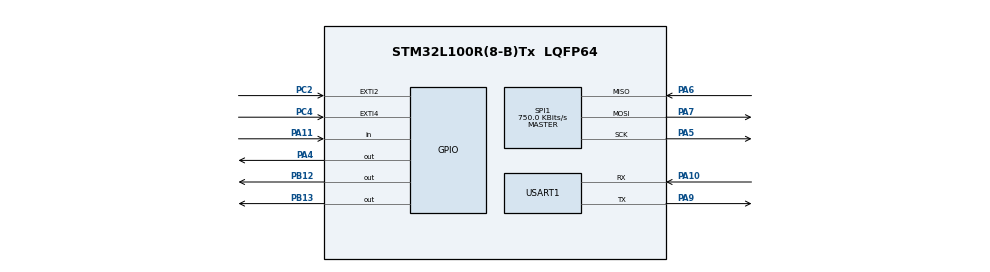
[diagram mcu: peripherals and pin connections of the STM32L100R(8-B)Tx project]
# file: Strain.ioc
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Mcu.Family=STM32L1
Mcu.Name=STM32L100R(8-B)Tx
Mcu.Package=LQFP64
NVIC.EXTI2_IRQn=true\:3\:0\:true\:false\:true\:true
NVIC.EXTI4_IRQn=true\:2\:0\:true\:false\:true\:true
NVIC.PriorityGroup=NVIC_PRIORITYGROUP_4
NVIC.RCC_IRQn=true\:0\:0\:false\:false\:true\:true
NVIC.SPI1_IRQn=true\:1\:0\:true\:false\:true\:true
NVIC.TIM3_IRQn=true\:4\:0\:true\:false\:true\:true
NVIC.USART1_IRQn=true\:5\:0\:true\:false\:true\:true
PA10.Mode=Asynchronous
PA10.Signal=USART1_RX
PA11.Signal=GPIO_Input
PA13.Mode=Serial_Wire
PA13.Signal=SYS_JTMS-SWDIO
PA14.Mode=Serial_Wire
PA14.Signal=SYS_JTCK-SWCLK
PA4.Signal=GPIO_Output
PA5.Mode=Full_Duplex_Master
PA5.Signal=SPI1_SCK
PA6.Mode=Full_Duplex_Master
PA6.Signal=SPI1_MISO
PA7.Mode=Full_Duplex_Master
PA7.Signal=SPI1_MOSI
PA9.Mode=Asynchronous
PA9.Signal=USART1_TX
PB12.Signal=GPIO_Output
PB13.Signal=GPIO_Output
PC2.GPIO_ModeDefaultEXTI=GPIO_MODE_IT_RISING
PC2.Signal=GPXTI2
PC4.GPIO_ModeDefaultEXTI=GPIO_MODE_IT_FALLING
PC4.Signal=GPXTI4
PH0-OSC_IN.Mode=HSE-External-Oscillator
PH0-OSC_IN.Signal=RCC_OSC_IN
PH1-OSC_OUT.Mode=HSE-External-Oscillator
PH1-OSC_OUT.Signal=RCC_OSC_OUT
ProjectManager.HeapSize=0x200
ProjectManager.StackSize=0x400
ProjectManager.TargetToolchain=MDK-ARM V5
RCC.48MHZClocksFreq_Value=24000000
RCC.AHBFreq_Value=24000000
RCC.APB1Freq_Value=24000000
RCC.APB1TimFreq_Value=24000000
RCC.APB2Freq_Value=24000000
RCC.APB2TimFreq_Value=24000000
RCC.HCLKFreq_Value=24000000
RCC.HSE_VALUE=8000000
RCC.HSI_VALUE=16000000
RCC.LSE_VALUE=32768
RCC.MSI_VALUE=2097000
RCC.PLLMUL=RCC_PLL_MUL6
RCC.PLLSourceVirtual=RCC_PLLSOURCE_HSE
RCC.SYSCLKFreq_VALUE=24000000
RCC.SYSCLKSource=RCC_SYSCLKSOURCE_PLLCLK
RCC.VCOOutputFreq_Value=48000000
SPI1.BaudRatePrescaler=SPI_BAUDRATEPRESCALER_32
SPI1.CLKPhase=SPI_PHASE_2EDGE
SPI1.CalculateBaudRate=750.0 KBits/s
SPI1.Direction=SPI_DIRECTION_2LINES
SPI1.Mode=SPI_MODE_MASTER
SPI1.VirtualType=VM_MASTER
TIM3.Period=999
TIM3.Prescaler=23
TIM3.TIM_MasterOutputTrigger=TIM_TRGO_UPDATE
USART1.VirtualMode=VM_ASYNC
VP_TIM3_VS_ClockSourceINT.Mode=Internal
board=Strain

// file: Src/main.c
/**
  ******************************************************************************
  * @file           : main.c
  * @brief          : Main program body
  ******************************************************************************
  ** This notice applies to any and all portions of this file
  * that are not between comment pairs USER CODE BEGIN and
  * USER CODE END. Other portions of this file, whether
  * inserted by the user or by software development tools
  * are owned by their respective copyright owners.
  *
  * COPYRIGHT(c) 2018 STMicroelectronics
  *
  * Redistribution and use in source and binary forms, with or without modification,
  * are permitted provided that the following conditions are met:
  *   1. Redistributions of source code must retain the above copyright notice,
  *      this list of conditions and the following disclaimer.
  *   2. Redistributions in binary form must reproduce the above copyright notice,
  *      this list of conditions and the following disclaimer in the documentation
  *      and/or other materials provided with the distribution.
  *   3. Neither the name of STMicroelectronics nor the names of its contributors
  *      may be used to endorse or promote products derived from this software
  *      without specific prior written permission.
  *
  * THIS SOFTWARE IS PROVIDED BY THE COPYRIGHT HOLDERS AND CONTRIBUTORS "AS IS"
  * AND ANY EXPRESS OR IMPLIED WARRANTIES, INCLUDING, BUT NOT LIMITED TO, THE
  * IMPLIED WARRANTIES OF MERCHANTABILITY AND FITNESS FOR A PARTICULAR PURPOSE ARE
  * DISCLAIMED. IN NO EVENT SHALL THE COPYRIGHT HOLDER OR CONTRIBUTORS BE LIABLE
  * FOR ANY DIRECT, INDIRECT, INCIDENTAL, SPECIAL, EXEMPLARY, OR CONSEQUENTIAL
  * DAMAGES (INCLUDING, BUT NOT LIMITED TO, PROCUREMENT OF SUBSTITUTE GOODS OR
  * SERVICES; LOSS OF USE, DATA, OR PROFITS; OR BUSINESS INTERRUPTION) HOWEVER
  * CAUSED AND ON ANY THEORY OF LIABILITY, WHETHER IN CONTRACT, STRICT LIABILITY,
  * OR TORT (INCLUDING NEGLIGENCE OR OTHERWISE) ARISING IN ANY WAY OUT OF THE USE
  * OF THIS SOFTWARE, EVEN IF ADVISED OF THE POSSIBILITY OF SUCH DAMAGE.
  *
  ******************************************************************************
  */
#include "main.h"
#include "stm32l1xx_hal.h"

SPI_HandleTypeDef hspi1;

TIM_HandleTypeDef htim3;

UART_HandleTypeDef huart1;

/* USER CODE BEGIN PV */
/* Private variables ---------------------------------------------------------*/
#define    DWT_CYCCNT    *(volatile unsigned long *)0xE0001004
#define    DWT_CONTROL   *(volatile unsigned long *)0xE0001000
#define    SCB_DEMCR     *(volatile unsigned long *)0xE000EDFC
uint32_t count_tic = 0;
uint8_t button_flag = 0;
uint8_t receive_arr[4];
/* USER CODE END PV */

void SystemClock_Config(void);
static void MX_GPIO_Init(void);
static void MX_USART1_UART_Init(void);
static void MX_SPI1_Init(void);
static void MX_TIM3_Init(void);

/* USER CODE BEGIN PFP */
/* Private function prototypes -----------------------------------------------*/
void ADC_Config(void);

/* USER CODE END PFP */

int main(void)
{

  /* MCU Configuration----------------------------------------------------------*/

  /* Reset of all peripherals, Initializes the Flash interface and the Systick. */
  HAL_Init();

  /* Configure the system clock */
  SystemClock_Config();

  /* Initialize all configured peripherals */
	MX_TIM3_Init();
  MX_GPIO_Init();
  MX_USART1_UART_Init();
  MX_SPI1_Init();

  /* USER CODE BEGIN 2 */
	//HAL_TIM_Base_Start(&htim3);
	HAL_TIM_Base_Start_IT(&htim3);

	HAL_GPIO_WritePin(GPIOA, GPIO_PIN_4, GPIO_PIN_RESET); // CS = 0
	ADC_Config();

  /* USER CODE END 2 */

  /* Infinite loop */
  while (1)
  {

  }

}

void SystemClock_Config(void)
{

  RCC_OscInitTypeDef RCC_OscInitStruct;
  RCC_ClkInitTypeDef RCC_ClkInitStruct;

    /**Configure the main internal regulator output voltage
    */
  __HAL_PWR_VOLTAGESCALING_CONFIG(PWR_REGULATOR_VOLTAGE_SCALE1);

    /**Initializes the CPU, AHB and APB busses clocks
    */
  RCC_OscInitStruct.OscillatorType = RCC_OSCILLATORTYPE_HSE;
  RCC_OscInitStruct.HSEState = RCC_HSE_ON;
  RCC_OscInitStruct.PLL.PLLState = RCC_PLL_ON;
  RCC_OscInitStruct.PLL.PLLSource = RCC_PLLSOURCE_HSE;
  RCC_OscInitStruct.PLL.PLLMUL = RCC_PLL_MUL4;
  RCC_OscInitStruct.PLL.PLLDIV = RCC_PLL_DIV2;
  if (HAL_RCC_OscConfig(&RCC_OscInitStruct) != HAL_OK)
  {
    _Error_Handler(__FILE__, __LINE__);
  }

    /**Initializes the CPU, AHB and APB busses clocks
    */
  RCC_ClkInitStruct.ClockType = RCC_CLOCKTYPE_HCLK|RCC_CLOCKTYPE_SYSCLK
                              |RCC_CLOCKTYPE_PCLK1|RCC_CLOCKTYPE_PCLK2;
  RCC_ClkInitStruct.SYSCLKSource = RCC_SYSCLKSOURCE_PLLCLK;
  RCC_ClkInitStruct.AHBCLKDivider = RCC_SYSCLK_DIV1;
  RCC_ClkInitStruct.APB1CLKDivider = RCC_HCLK_DIV1;
  RCC_ClkInitStruct.APB2CLKDivider = RCC_HCLK_DIV1;

  if (HAL_RCC_ClockConfig(&RCC_ClkInitStruct, FLASH_LATENCY_1) != HAL_OK)
  {
    _Error_Handler(__FILE__, __LINE__);
  }

    /**Configure the Systick interrupt time
    */
  HAL_SYSTICK_Config(HAL_RCC_GetHCLKFreq()/1000);

    /**Configure the Systick
    */
  HAL_SYSTICK_CLKSourceConfig(SYSTICK_CLKSOURCE_HCLK);

  /* SysTick_IRQn interrupt configuration */
  HAL_NVIC_SetPriority(SysTick_IRQn, 0, 0);
}

/* SPI1 init function */
static void MX_SPI1_Init(void)
{

  /* SPI1 parameter configuration*/
  hspi1.Instance = SPI1;
  hspi1.Init.Mode = SPI_MODE_MASTER;
  hspi1.Init.Direction = SPI_DIRECTION_2LINES;
  hspi1.Init.DataSize = SPI_DATASIZE_8BIT;
  hspi1.Init.CLKPolarity = SPI_POLARITY_LOW;
  hspi1.Init.CLKPhase = SPI_PHASE_2EDGE;
  hspi1.Init.NSS = SPI_NSS_SOFT;
  hspi1.Init.BaudRatePrescaler = SPI_BAUDRATEPRESCALER_16;
  hspi1.Init.FirstBit = SPI_FIRSTBIT_MSB;
  hspi1.Init.TIMode = SPI_TIMODE_DISABLE;
  hspi1.Init.CRCCalculation = SPI_CRCCALCULATION_DISABLE;
  hspi1.Init.CRCPolynomial = 10;
  if (HAL_SPI_Init(&hspi1) != HAL_OK)
  {
    _Error_Handler(__FILE__, __LINE__);
  }

}

/* TIM3 init function */
static void MX_TIM3_Init(void)
{

  TIM_ClockConfigTypeDef sClockSourceConfig;
  TIM_MasterConfigTypeDef sMasterConfig;

  htim3.Instance = TIM3;
  htim3.Init.Prescaler = 159;
  htim3.Init.CounterMode = TIM_COUNTERMODE_UP;
  htim3.Init.Period = 100;
  htim3.Init.ClockDivision = TIM_CLOCKDIVISION_DIV1;
  if (HAL_TIM_Base_Init(&htim3) != HAL_OK)
  {
    _Error_Handler(__FILE__, __LINE__);
  }

  //sClockSourceConfig.ClockSource = TIM_CLOCKSOURCE_INTERNAL;
  if (HAL_TIM_ConfigClockSource(&htim3, &sClockSourceConfig) != HAL_OK)
  {
    _Error_Handler(__FILE__, __LINE__);
  }

  sMasterConfig.MasterOutputTrigger = TIM_TRGO_UPDATE;
  sMasterConfig.MasterSlaveMode = TIM_MASTERSLAVEMODE_DISABLE;
  if (HAL_TIMEx_MasterConfigSynchronization(&htim3, &sMasterConfig) != HAL_OK)
  {
    _Error_Handler(__FILE__, __LINE__);
  }

}

/* USART1 init function */
static void MX_USART1_UART_Init(void)
{

  huart1.Instance = USART1;
  huart1.Init.BaudRate = 460800;
  huart1.Init.WordLength = UART_WORDLENGTH_8B;
  huart1.Init.StopBits = UART_STOPBITS_1;
  huart1.Init.Parity = UART_PARITY_NONE;
  huart1.Init.Mode = UART_MODE_TX_RX;
  huart1.Init.HwFlowCtl = UART_HWCONTROL_NONE;
  huart1.Init.OverSampling = UART_OVERSAMPLING_16;
  if (HAL_UART_Init(&huart1) != HAL_OK)
  {
    _Error_Handler(__FILE__, __LINE__);
  }

}

/** Configure pins as
        * Analog
        * Input
        * Output
        * EVENT_OUT
        * EXTI
*/
static void MX_GPIO_Init(void)
{

  GPIO_InitTypeDef GPIO_InitStruct;

  /* GPIO Ports Clock Enable */
  __HAL_RCC_GPIOH_CLK_ENABLE();
  __HAL_RCC_GPIOC_CLK_ENABLE();
  __HAL_RCC_GPIOA_CLK_ENABLE();
  __HAL_RCC_GPIOB_CLK_ENABLE();

  /*Configure GPIO pin Output Level */
  HAL_GPIO_WritePin(GPIOA, GPIO_PIN_4, GPIO_PIN_RESET);

  /*Configure GPIO pin Output Level */
  HAL_GPIO_WritePin(GPIOB, GPIO_PIN_12|GPIO_PIN_13, GPIO_PIN_RESET);

  /*Configure GPIO pin : PC2 */
  GPIO_InitStruct.Pin = GPIO_PIN_2;
  GPIO_InitStruct.Mode = GPIO_MODE_IT_RISING;
  GPIO_InitStruct.Pull = GPIO_NOPULL;
  HAL_GPIO_Init(GPIOC, &GPIO_InitStruct);

  /*Configure GPIO pin : PA4 */
  GPIO_InitStruct.Pin = GPIO_PIN_4;
  GPIO_InitStruct.Mode = GPIO_MODE_OUTPUT_PP;
  GPIO_InitStruct.Pull = GPIO_NOPULL;
  GPIO_InitStruct.Speed = GPIO_SPEED_FREQ_LOW;
  HAL_GPIO_Init(GPIOA, &GPIO_InitStruct);

  /*Configure GPIO pin : PC4 */
  GPIO_InitStruct.Pin = GPIO_PIN_4;
  GPIO_InitStruct.Mode = GPIO_MODE_IT_FALLING;
  GPIO_InitStruct.Pull = GPIO_NOPULL;
  HAL_GPIO_Init(GPIOC, &GPIO_InitStruct);

  /*Configure GPIO pins : PB12 PB13 */
  GPIO_InitStruct.Pin = GPIO_PIN_12|GPIO_PIN_13;
  GPIO_InitStruct.Mode = GPIO_MODE_OUTPUT_PP;
  GPIO_InitStruct.Pull = GPIO_NOPULL;
  GPIO_InitStruct.Speed = GPIO_SPEED_FREQ_HIGH;
  HAL_GPIO_Init(GPIOB, &GPIO_InitStruct);

  /*Configure GPIO pin : PA11 */
  GPIO_InitStruct.Pin = GPIO_PIN_11;
  GPIO_InitStruct.Mode = GPIO_MODE_INPUT;
  GPIO_InitStruct.Pull = GPIO_NOPULL;
  HAL_GPIO_Init(GPIOA, &GPIO_InitStruct);

  /* EXTI interrupt init*/
  HAL_NVIC_SetPriority(EXTI2_IRQn, 4, 0);
  HAL_NVIC_EnableIRQ(EXTI2_IRQn);

  HAL_NVIC_SetPriority(EXTI4_IRQn, 2, 0);
  HAL_NVIC_EnableIRQ(EXTI4_IRQn);

}

/* USER CODE BEGIN 4 */
void ADC_Config(void)
{
	uint8_t wreg = 0x53, data = 0x00, byte1 = 0x00, sync = 0xFC, wakeup = 0x00, rreg = 0x10, rxData = 0x01, rst = 0xFE;
	uint8_t rregADCon = 0x12, adcon_data = 0x00;

	EXTI->IMR |= EXTI_IMR_MR10; //Mask on EXTI4 (Line 10), DRDY interrupt is off

	HAL_SPI_Transmit(&hspi1, &rst, 1, 10); //RESET

	HAL_SPI_Transmit(&hspi1, &sync, 1, 10); //SYNC
	HAL_SPI_Transmit(&hspi1, &wakeup, 1, 10); //WAKE UP

	HAL_SPI_Transmit(&hspi1, &rreg, 1, 10); //RREG STATUS first byte
	HAL_SPI_Transmit(&hspi1, &byte1, 1, 10); //RREG STATUS second byte
	HAL_SPI_Receive(&hspi1, &rxData, 1, 10);  //get STATUS bits

	HAL_SPI_Transmit(&hspi1, &rregADCon, 1, 10); //RREG ADCON first byte
	HAL_SPI_Transmit(&hspi1, &byte1, 1, 10); //RREG ADCON second byte
	HAL_SPI_Receive(&hspi1, &adcon_data, 1, 10);  //get ADCON bits

	data = 0xD0; //Data rate = 7500 SpS = 7500 Hz
	HAL_SPI_Transmit(&hspi1, &wreg, 1, 10); //WREG DRATE first byte
	HAL_SPI_Transmit(&hspi1, &byte1, 1, 10); //WREG DRATE second byte
	HAL_SPI_Transmit(&hspi1, &data, 1, 10); //WREG DRATE third byte

	EXTI->IMR &= ~(EXTI_IMR_MR10); //Mask on EXTI4 (Line 10), DRDY interrupt is on
}
/* USER CODE END 4 */

void _Error_Handler(char *file, int line)
{
  while(1)
  {
  }
}

/************************ (C) COPYRIGHT STMicroelectronics *****END OF FILE****/
